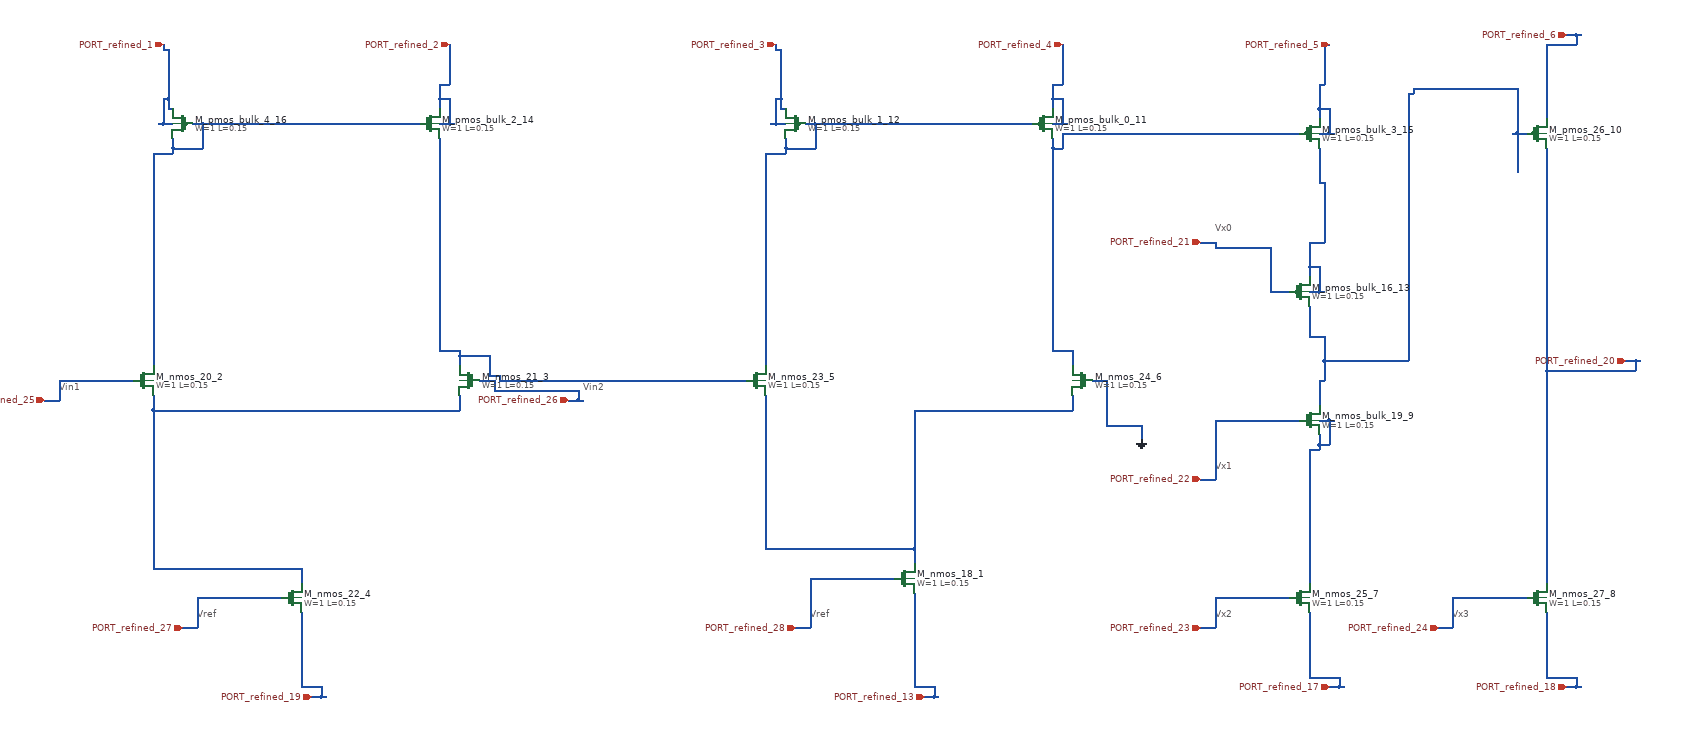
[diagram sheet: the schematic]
v {xschem version=3.4.8 file_version=1.2}
G {}
K {}
V {}
S {}
E {}
C {devices/gnd.sym} 2660 1000 0 0 {name="l_gnd_7_0" lab="GND"}
C {sky130_fd_pr/nfet3_01v8.sym} 2180 1280 0 0 {name="M_nmos_18_1"
W=1
L=0.15
body=GND
nf=1
mult=1
ad="expr('int((@nf + 1)/2) * @W / @nf * 0.29')"
pd="expr('2*int((@nf + 1)/2) * (@W / @nf + 0.29)')"
as="expr('int((@nf + 2)/2) * @W / @nf * 0.29')"
ps="expr('2*int((@nf + 2)/2) * (@W / @nf + 0.29)')"
nrd="expr('0.29 / @W ')" nrs="expr('0.29 / @W ')"
sa=0 sb=0 sd=0
model=nfet_01v8
spiceprefix=X
}
C {sky130_fd_pr/nfet3_01v8.sym} 640 880 0 0 {name="M_nmos_20_2"
W=1
L=0.15
body=GND
nf=1
mult=1
ad="expr('int((@nf + 1)/2) * @W / @nf * 0.29')"
pd="expr('2*int((@nf + 1)/2) * (@W / @nf + 0.29)')"
as="expr('int((@nf + 2)/2) * @W / @nf * 0.29')"
ps="expr('2*int((@nf + 2)/2) * (@W / @nf + 0.29)')"
nrd="expr('0.29 / @W ')" nrs="expr('0.29 / @W ')"
sa=0 sb=0 sd=0
model=nfet_01v8
spiceprefix=X
}
C {sky130_fd_pr/nfet3_01v8.sym} 1300 880 0 1 {name="M_nmos_21_3"
W=1
L=0.15
body=GND
nf=1
mult=1
ad="expr('int((@nf + 1)/2) * @W / @nf * 0.29')"
pd="expr('2*int((@nf + 1)/2) * (@W / @nf + 0.29)')"
as="expr('int((@nf + 2)/2) * @W / @nf * 0.29')"
ps="expr('2*int((@nf + 2)/2) * (@W / @nf + 0.29)')"
nrd="expr('0.29 / @W ')" nrs="expr('0.29 / @W ')"
sa=0 sb=0 sd=0
model=nfet_01v8
spiceprefix=X
}
C {sky130_fd_pr/nfet3_01v8.sym} 940 1320 0 0 {name="M_nmos_22_4"
W=1
L=0.15
body=GND
nf=1
mult=1
ad="expr('int((@nf + 1)/2) * @W / @nf * 0.29')"
pd="expr('2*int((@nf + 1)/2) * (@W / @nf + 0.29)')"
as="expr('int((@nf + 2)/2) * @W / @nf * 0.29')"
ps="expr('2*int((@nf + 2)/2) * (@W / @nf + 0.29)')"
nrd="expr('0.29 / @W ')" nrs="expr('0.29 / @W ')"
sa=0 sb=0 sd=0
model=nfet_01v8
spiceprefix=X
}
C {sky130_fd_pr/nfet3_01v8.sym} 1880 880 0 0 {name="M_nmos_23_5"
W=1
L=0.15
body=GND
nf=1
mult=1
ad="expr('int((@nf + 1)/2) * @W / @nf * 0.29')"
pd="expr('2*int((@nf + 1)/2) * (@W / @nf + 0.29)')"
as="expr('int((@nf + 2)/2) * @W / @nf * 0.29')"
ps="expr('2*int((@nf + 2)/2) * (@W / @nf + 0.29)')"
nrd="expr('0.29 / @W ')" nrs="expr('0.29 / @W ')"
sa=0 sb=0 sd=0
model=nfet_01v8
spiceprefix=X
}
C {sky130_fd_pr/nfet3_01v8.sym} 2540 880 0 1 {name="M_nmos_24_6"
W=1
L=0.15
body=GND
nf=1
mult=1
ad="expr('int((@nf + 1)/2) * @W / @nf * 0.29')"
pd="expr('2*int((@nf + 1)/2) * (@W / @nf + 0.29)')"
as="expr('int((@nf + 2)/2) * @W / @nf * 0.29')"
ps="expr('2*int((@nf + 2)/2) * (@W / @nf + 0.29)')"
nrd="expr('0.29 / @W ')" nrs="expr('0.29 / @W ')"
sa=0 sb=0 sd=0
model=nfet_01v8
spiceprefix=X
}
C {sky130_fd_pr/nfet3_01v8.sym} 2980 1320 0 0 {name="M_nmos_25_7"
W=1
L=0.15
body=GND
nf=1
mult=1
ad="expr('int((@nf + 1)/2) * @W / @nf * 0.29')"
pd="expr('2*int((@nf + 1)/2) * (@W / @nf + 0.29)')"
as="expr('int((@nf + 2)/2) * @W / @nf * 0.29')"
ps="expr('2*int((@nf + 2)/2) * (@W / @nf + 0.29)')"
nrd="expr('0.29 / @W ')" nrs="expr('0.29 / @W ')"
sa=0 sb=0 sd=0
model=nfet_01v8
spiceprefix=X
}
C {sky130_fd_pr/nfet3_01v8.sym} 3460 1320 0 0 {name="M_nmos_27_8"
W=1
L=0.15
body=GND
nf=1
mult=1
ad="expr('int((@nf + 1)/2) * @W / @nf * 0.29')"
pd="expr('2*int((@nf + 1)/2) * (@W / @nf + 0.29)')"
as="expr('int((@nf + 2)/2) * @W / @nf * 0.29')"
ps="expr('2*int((@nf + 2)/2) * (@W / @nf + 0.29)')"
nrd="expr('0.29 / @W ')" nrs="expr('0.29 / @W ')"
sa=0 sb=0 sd=0
model=nfet_01v8
spiceprefix=X
}
C {sky130_fd_pr/nfet_01v8.sym} 3000 960 0 0 {name="M_nmos_bulk_19_9"
W=1
L=0.15
nf=1 
mult=1
ad="expr('int((@nf + 1)/2) * @W / @nf * 0.29')"
pd="expr('2*int((@nf + 1)/2) * (@W / @nf + 0.29)')"
as="expr('int((@nf + 2)/2) * @W / @nf * 0.29')"
ps="expr('2*int((@nf + 2)/2) * (@W / @nf + 0.29)')"
nrd="expr('0.29 / @W ')" nrs="expr('0.29 / @W ')"
sa=0 sb=0 sd=0
model=nfet_01v8
spiceprefix=X
}
C {sky130_fd_pr/pfet3_01v8.sym} 3460 380 0 0 {name="M_pmos_26_10"
W=1
L=0.15
body=VDD
nf=1
mult=1
ad="expr('int((@nf + 1)/2) * @W / @nf * 0.29')"
pd="expr('2*int((@nf + 1)/2) * (@W / @nf + 0.29)')"
as="expr('int((@nf + 2)/2) * @W / @nf * 0.29')"
ps="expr('2*int((@nf + 2)/2) * (@W / @nf + 0.29)')"
nrd="expr('0.29 / @W ')" nrs="expr('0.29 / @W ')"
sa=0 sb=0 sd=0
model=pfet_01v8
spiceprefix=X
}
C {sky130_fd_pr/pfet_01v8.sym} 2460 360 0 0 {name="M_pmos_bulk_0_11"
W=1
L=0.15
nf=1
mult=1
ad="expr('int((@nf + 1)/2) * @W / @nf * 0.29')"
pd="expr('2*int((@nf + 1)/2) * (@W / @nf + 0.29)')"
as="expr('int((@nf + 2)/2) * @W / @nf * 0.29')"
ps="expr('2*int((@nf + 2)/2) * (@W / @nf + 0.29)')"
nrd="expr('0.29 / @W ')" nrs="expr('0.29 / @W ')"
sa=0 sb=0 sd=0
model=pfet_01v8
spiceprefix=X
}
C {sky130_fd_pr/pfet_01v8.sym} 1960 360 0 1 {name="M_pmos_bulk_1_12"
W=1
L=0.15
nf=1
mult=1
ad="expr('int((@nf + 1)/2) * @W / @nf * 0.29')"
pd="expr('2*int((@nf + 1)/2) * (@W / @nf + 0.29)')"
as="expr('int((@nf + 2)/2) * @W / @nf * 0.29')"
ps="expr('2*int((@nf + 2)/2) * (@W / @nf + 0.29)')"
nrd="expr('0.29 / @W ')" nrs="expr('0.29 / @W ')"
sa=0 sb=0 sd=0
model=pfet_01v8
spiceprefix=X
}
C {sky130_fd_pr/pfet_01v8.sym} 2980 700 0 0 {name="M_pmos_bulk_16_13"
W=1
L=0.15
nf=1
mult=1
ad="expr('int((@nf + 1)/2) * @W / @nf * 0.29')"
pd="expr('2*int((@nf + 1)/2) * (@W / @nf + 0.29)')"
as="expr('int((@nf + 2)/2) * @W / @nf * 0.29')"
ps="expr('2*int((@nf + 2)/2) * (@W / @nf + 0.29)')"
nrd="expr('0.29 / @W ')" nrs="expr('0.29 / @W ')"
sa=0 sb=0 sd=0
model=pfet_01v8
spiceprefix=X
}
C {sky130_fd_pr/pfet_01v8.sym} 1220 360 0 0 {name="M_pmos_bulk_2_14"
W=1
L=0.15
nf=1
mult=1
ad="expr('int((@nf + 1)/2) * @W / @nf * 0.29')"
pd="expr('2*int((@nf + 1)/2) * (@W / @nf + 0.29)')"
as="expr('int((@nf + 2)/2) * @W / @nf * 0.29')"
ps="expr('2*int((@nf + 2)/2) * (@W / @nf + 0.29)')"
nrd="expr('0.29 / @W ')" nrs="expr('0.29 / @W ')"
sa=0 sb=0 sd=0
model=pfet_01v8
spiceprefix=X
}
C {sky130_fd_pr/pfet_01v8.sym} 3000 380 0 0 {name="M_pmos_bulk_3_15"
W=1
L=0.15
nf=1
mult=1
ad="expr('int((@nf + 1)/2) * @W / @nf * 0.29')"
pd="expr('2*int((@nf + 1)/2) * (@W / @nf + 0.29)')"
as="expr('int((@nf + 2)/2) * @W / @nf * 0.29')"
ps="expr('2*int((@nf + 2)/2) * (@W / @nf + 0.29)')"
nrd="expr('0.29 / @W ')" nrs="expr('0.29 / @W ')"
sa=0 sb=0 sd=0
model=pfet_01v8
spiceprefix=X
}
C {sky130_fd_pr/pfet_01v8.sym} 720 360 0 1 {name="M_pmos_bulk_4_16"
W=1
L=0.15
nf=1
mult=1
ad="expr('int((@nf + 1)/2) * @W / @nf * 0.29')"
pd="expr('2*int((@nf + 1)/2) * (@W / @nf + 0.29)')"
as="expr('int((@nf + 2)/2) * @W / @nf * 0.29')"
ps="expr('2*int((@nf + 2)/2) * (@W / @nf + 0.29)')"
nrd="expr('0.29 / @W ')" nrs="expr('0.29 / @W ')"
sa=0 sb=0 sd=0
model=pfet_01v8
spiceprefix=X
}
C {devices/ipin.sym} 980 1520 0 0 {name="p_port_10_17" lab="PORT_refined_19"}
C {devices/ipin.sym} 1920 200 0 0 {name="p_port_11_18" lab="PORT_refined_3"}
C {devices/ipin.sym} 3640 840 0 0 {name="p_port_12_19" lab="PORT_refined_20"}
C {devices/ipin.sym} 2500 200 0 0 {name="p_port_13_20" lab="PORT_refined_4"}
C {devices/ipin.sym} 1260 200 0 0 {name="p_port_14_21" lab="PORT_refined_2"}
C {devices/ipin.sym} 3520 180 0 0 {name="p_port_15_22" lab="PORT_refined_6"}
C {devices/ipin.sym} 680 200 0 0 {name="p_port_17_23" lab="PORT_refined_1"}
C {devices/ipin.sym} 440 920 0 0 {name="p_port_28_24" lab="PORT_refined_25"}
T {Vin1} 470 880 0 0 0.25 0.25 {}
C {devices/ipin.sym} 1500 920 0 0 {name="p_port_29_25" lab="PORT_refined_26"}
T {Vin2} 1530 880 0 0 0.25 0.25 {}
C {devices/ipin.sym} 720 1380 0 0 {name="p_port_30_26" lab="PORT_refined_27"}
T {Vref} 750 1340 0 0 0.25 0.25 {}
C {devices/ipin.sym} 1960 1380 0 0 {name="p_port_31_27" lab="PORT_refined_28"}
T {Vref} 1990 1340 0 0 0.25 0.25 {}
C {devices/ipin.sym} 2780 600 0 0 {name="p_port_32_28" lab="PORT_refined_21"}
T {Vx0} 2810 560 0 0 0.25 0.25 {}
C {devices/ipin.sym} 2780 1080 0 0 {name="p_port_33_29" lab="PORT_refined_22"}
T {Vx1} 2810 1040 0 0 0.25 0.25 {}
C {devices/ipin.sym} 2780 1380 0 0 {name="p_port_34_30" lab="PORT_refined_23"}
T {Vx2} 2810 1340 0 0 0.25 0.25 {}
C {devices/ipin.sym} 3260 1380 0 0 {name="p_port_35_31" lab="PORT_refined_24"}
T {Vx3} 3290 1340 0 0 0.25 0.25 {}
C {devices/ipin.sym} 3520 1500 0 0 {name="p_port_5_32" lab="PORT_refined_18"}
C {devices/ipin.sym} 2220 1520 0 0 {name="p_port_6_33" lab="PORT_refined_13"}
C {devices/ipin.sym} 3040 1500 0 0 {name="p_port_8_34" lab="PORT_refined_17"}
C {devices/ipin.sym} 3040 200 0 0 {name="p_port_9_35" lab="PORT_refined_5"}
N 2590 970 2660 970 {}
N 2560 880 2590 880 {}
N 2590 970 2590 880 {}
N 2660 1000 2660 970 {}
N 670 360 680 360 {}
N 680 360 700 360 {}
N 690 330 700 330 {}
N 680 310 690 310 {}
N 680 210 690 210 {}
N 680 360 680 310 {}
N 680 210 680 200 {}
N 690 330 690 310 {}
N 690 310 690 210 {}
N 1900 420 1940 420 {}
N 1940 410 2000 410 {}
N 1980 360 2000 360 {}
N 2000 360 2440 360 {}
N 1900 850 1900 420 {}
N 1940 420 1940 410 {}
N 1940 410 1940 390 {}
N 2000 410 2000 360 {}
N 2480 820 2520 820 {}
N 2480 410 2500 410 {}
N 2500 380 2980 380 {}
N 2480 820 2480 410 {}
N 2480 410 2480 390 {}
N 2500 410 2500 380 {}
N 2520 850 2520 820 {}
N 1900 1220 2200 1220 {}
N 2200 940 2520 940 {}
N 1900 1220 1900 910 {}
N 2200 1250 2200 1220 {}
N 2200 1220 2200 940 {}
N 2520 940 2520 910 {}
N 2220 1520 2240 1520 {}
N 2240 1520 2250 1520 {}
N 2200 1500 2240 1500 {}
N 2200 1500 2200 1310 {}
N 2240 1520 2240 1500 {}
N 3000 700 3020 700 {}
N 3020 700 3030 700 {}
N 3000 650 3020 650 {}
N 3000 600 3030 600 {}
N 3020 480 3030 480 {}
N 3000 670 3000 650 {}
N 3000 650 3000 600 {}
N 3020 700 3020 650 {}
N 3020 480 3020 410 {}
N 3030 600 3030 480 {}
N 3020 880 3030 880 {}
N 3030 840 3200 840 {}
N 3000 790 3030 790 {}
N 3410 380 3420 380 {}
N 3420 380 3440 380 {}
N 3200 300 3210 300 {}
N 3210 290 3420 290 {}
N 3000 790 3000 730 {}
N 3020 930 3020 880 {}
N 3030 880 3030 840 {}
N 3030 840 3030 790 {}
N 3200 840 3200 300 {}
N 3210 300 3210 290 {}
N 3420 460 3420 380 {}
N 3420 380 3420 290 {}
N 3000 1020 3020 1020 {}
N 3020 1010 3040 1010 {}
N 3020 960 3040 960 {}
N 3040 960 3050 960 {}
N 3000 1290 3000 1020 {}
N 3020 1020 3020 1010 {}
N 3020 1010 3020 990 {}
N 3040 1010 3040 960 {}
N 3040 1500 3060 1500 {}
N 3060 1500 3070 1500 {}
N 3000 1480 3060 1480 {}
N 3000 1480 3000 1350 {}
N 3060 1500 3060 1480 {}
N 3520 1500 3540 1500 {}
N 3540 1500 3550 1500 {}
N 3480 1480 3540 1480 {}
N 3480 1480 3480 1350 {}
N 3540 1500 3540 1480 {}
N 980 1520 1000 1520 {}
N 1000 1520 1010 1520 {}
N 960 1500 1000 1500 {}
N 960 1500 960 1350 {}
N 1000 1520 1000 1500 {}
N 1240 360 1260 360 {}
N 1260 360 1270 360 {}
N 1240 310 1260 310 {}
N 1240 280 1260 280 {}
N 1240 330 1240 310 {}
N 1240 310 1240 280 {}
N 1260 360 1260 310 {}
N 1260 280 1260 200 {}
N 3480 860 3660 860 {}
N 3640 840 3660 840 {}
N 3660 840 3670 840 {}
N 3480 1290 3480 860 {}
N 3480 860 3480 410 {}
N 3660 860 3660 840 {}
N 2920 700 2960 700 {}
N 2810 610 2920 610 {}
N 2780 600 2810 600 {}
N 2810 610 2810 600 {}
N 2920 700 2920 610 {}
N 2780 1080 2810 1080 {}
N 2810 960 2980 960 {}
N 2810 1080 2810 960 {}
N 2780 1380 2810 1380 {}
N 2810 1320 2960 1320 {}
N 2810 1380 2810 1320 {}
N 3260 1380 3290 1380 {}
N 3290 1320 3440 1320 {}
N 3290 1380 3290 1320 {}
N 440 920 470 920 {}
N 470 880 620 880 {}
N 470 920 470 880 {}
N 1500 920 1520 920 {}
N 1520 920 1530 920 {}
N 1350 900 1520 900 {}
N 1320 880 1350 880 {}
N 1350 900 1350 880 {}
N 1520 920 1520 900 {}
N 720 1380 750 1380 {}
N 750 1320 920 1320 {}
N 750 1380 750 1320 {}
N 1960 1380 1990 1380 {}
N 1990 1280 2160 1280 {}
N 1990 1380 1990 1280 {}
N 1910 360 1920 360 {}
N 1920 360 1940 360 {}
N 1930 330 1940 330 {}
N 1920 310 1930 310 {}
N 1920 210 1930 210 {}
N 1920 360 1920 310 {}
N 1920 210 1920 200 {}
N 1930 330 1930 310 {}
N 1930 310 1930 210 {}
N 2480 360 2500 360 {}
N 2500 360 2510 360 {}
N 2480 310 2500 310 {}
N 2480 280 2500 280 {}
N 2480 330 2480 310 {}
N 2480 310 2480 280 {}
N 2500 360 2500 310 {}
N 2500 280 2500 200 {}
N 3020 380 3040 380 {}
N 3040 380 3050 380 {}
N 3020 330 3040 330 {}
N 3020 280 3030 280 {}
N 3030 200 3040 200 {}
N 3020 350 3020 330 {}
N 3020 330 3020 280 {}
N 3030 280 3030 200 {}
N 3040 380 3040 330 {}
N 3480 200 3540 200 {}
N 3520 180 3540 180 {}
N 3540 180 3550 180 {}
N 3480 350 3480 200 {}
N 3540 200 3540 180 {}
N 660 420 700 420 {}
N 700 410 760 410 {}
N 740 360 760 360 {}
N 760 360 1200 360 {}
N 660 850 660 420 {}
N 700 420 700 410 {}
N 700 410 700 390 {}
N 760 410 760 360 {}
N 1360 880 1860 880 {}
N 1340 870 1360 870 {}
N 1280 830 1340 830 {}
N 1240 820 1280 820 {}
N 1240 820 1240 390 {}
N 1280 850 1280 830 {}
N 1280 830 1280 820 {}
N 1340 870 1340 830 {}
N 1360 880 1360 870 {}
N 660 1260 960 1260 {}
N 660 940 1280 940 {}
N 660 1260 660 940 {}
N 660 940 660 910 {}
N 960 1290 960 1260 {}
N 1280 940 1280 910 {}
